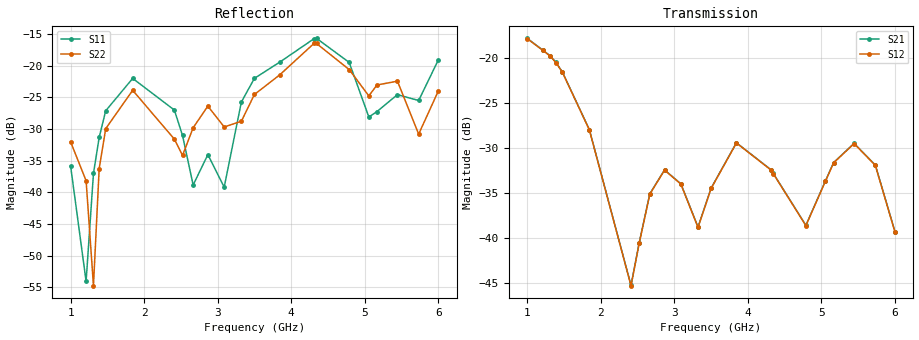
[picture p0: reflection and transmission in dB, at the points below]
!Agilent Technologies,E8364B,MY43040528,A.07.50.67
!Agilent E8364B: A.07.50.67
!Date: Sunday, March 01, 2026 23:14:05
!Correction: S11(Full 2 Port(1,2))
!S21(Full 2 Port(1,2))
!S12(Full 2 Port(1,2))
!S22(Full 2 Port(1,2))
!S2P File: Measurements: S11, S21, S12, S22:
# Hz S  dB  R 50
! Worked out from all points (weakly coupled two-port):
!   451 points, 1 GHz to 6 GHz, reference 50 ohm
!   highest |S21| = -17.83 dB at 1 GHz (marker M1); lowest = -45.2 dB at 2.411 GHz (marker M2)
!   lowest |S11| = -54.1 dB at 1.211 GHz (marker M3), VSWR 1.00, Z = 50.1 - j0.186 ohm
!   |S11| at or under -10 dB: start of sweep to end of sweep
!   |S22| runs from -54.8 to -16.5 dB; largest |S21 - S12| = 0.00047
!   S11 on the Smith chart (normalised r, x): 1 GHz: 1.03, +0.01; 4.311 GHz: 1.22, -0.29; 6 GHz: 0.96, -0.21
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1e9  -35.82 10.2  -17.83 29.1  -17.86 29.2  -32.03 -12.5
1.211111e9  -54.07 -70.1  -19.13 -34.5  -19.16 -34.5  -38.17 -30.7
1.311111e9  -37.03 -157.3  -19.76 -67.3  -19.79 -67.2  -54.75 -155.4
1.388889e9  -31.34 -178.6  -20.48 -93.6  -20.51 -93.5  -36.26 115.0
1.477778e9  -27.13 157.1  -21.57 -123.5  -21.59 -123.4  -29.95 85.9
1.844444e9  -22.02 78.0  -27.96 120.6  -27.98 120.7  -23.90 -8.7
2.411111e9  -27.02 -11.3  -45.25 -123.8  -45.28 -123.9  -31.61 -91.8
2.522222e9  -31.03 -25.0  -40.54 138.3  -40.57 138.3  -34.19 -74.1
2.666667e9  -38.85 3.5  -35.09 66.1  -35.12 66.1  -29.81 -62.3
2.866667e9  -34.06 31.7  -32.43 -16.0  -32.46 -16.0  -26.40 -99.4
3.088889e9  -39.20 68.1  -33.97 -96.8  -34.00 -96.8  -29.69 -136.7
3.322222e9  -25.75 81.3  -38.78 -135.3  -38.81 -135.3  -28.79 -110.2
3.5e9  -22.01 52.2  -34.46 -155.5  -34.49 -155.5  -24.56 -131.1
3.844444e9  -19.45 15.6  -29.42 86.2  -29.44 86.2  -21.46 -165.7
4.311111e9  -15.75 -45.9  -32.39 -83.2  -32.42 -83.2  -16.49 118.1
4.344444e9  -15.70 -51.0  -32.80 -95.1  -32.83 -95.1  -16.51 111.8
4.788889e9  -19.50 -119.0  -38.58 56.4  -38.62 56.4  -20.63 33.3
5.055556e9  -28.11 -119.6  -33.64 -100.7  -33.67 -100.7  -24.78 33.3
5.166667e9  -27.26 -92.7  -31.61 -153.7  -31.64 -153.7  -23.06 29.9
5.444444e9  -24.59 -108.8  -29.48 84.6  -29.51 84.6  -22.46 -20.3
5.733333e9  -25.51 -78.6  -31.89 -33.9  -31.93 -33.9  -30.82 -26.1
6e9  -19.12 -93.9  -39.28 -116.8  -39.31 -116.8  -24.02 -20.9
